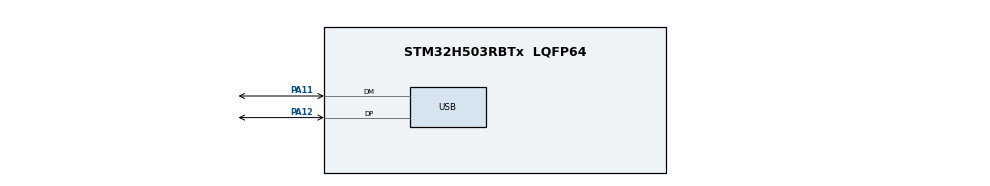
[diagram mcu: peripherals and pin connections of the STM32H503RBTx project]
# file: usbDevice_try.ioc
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Mcu.Family=STM32H5
Mcu.Name=STM32H503RBTx
Mcu.Package=LQFP64
NVIC.PriorityGroup=NVIC_PRIORITYGROUP_4
NVIC.USB_DRD_FS_IRQn=true\:0\:0\:false\:false\:true\:true\:true\:true
PA11.Mode=Device
PA11.Signal=USB_DM
PA12.Mode=Device
PA12.Signal=USB_DP
ProjectManager.HeapSize=0x600
ProjectManager.StackSize=0x800
ProjectManager.TargetToolchain=STM32CubeIDE
RCC.ADCFreq_Value=64000000
RCC.AHBFreq_Value=64000000
RCC.APB1Freq_Value=64000000
RCC.APB1TimFreq_Value=64000000
RCC.APB2Freq_Value=64000000
RCC.APB2TimFreq_Value=64000000
RCC.APB3Freq_Value=64000000
RCC.CSI_VALUE=4000000
RCC.CortexFreq_Value=64000000
RCC.EPOD_VALUE=32000000
RCC.HCLKFreq_Value=64000000
RCC.HSE_VALUE=25000000
RCC.HSI48_VALUE=48000000
RCC.HSI_VALUE=64000000
RCC.LSE_VALUE=32768
RCC.LSIRC_VALUE=32000
RCC.PLL1P=8
RCC.PLLM=8
RCC.PLLN=128
RCC.PLLSourceVirtual=RCC_PLL1_SOURCE_HSI
RCC.SYSCLKFreq_VALUE=64000000
RCC.SYSCLKSource=RCC_SYSCLKSOURCE_PLLCLK
RCC.USBFreq_Value=48000000
RCC.VCOOutputFreq_Value=512000000
USB.VirtualMode=Device_Only
VP_BOOTPATH_VS_BOOTPATH.Mode=BP_Activate
VP_CORTEX_M33_NS_VS_Hclk.Mode=Hclk_Mode
VP_MEMORYMAP_VS_MEMORYMAP.Mode=CurAppReg
VP_PWR_VS_DBSignals.Mode=DisableDeadBatterySignals
VP_PWR_VS_LPOM.Mode=PowerOptimisation
VP_PWR_VS_SECSignals.Mode=Security/Privilege
board=custom

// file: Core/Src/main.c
/* USER CODE BEGIN Header */
/**
 ******************************************************************************
 * @file           : main.c
 * @brief          : Main program body
 ******************************************************************************
 * @attention
 *
 * Copyright (c) 2024 STMicroelectronics.
 * All rights reserved.
 *
 * This software is licensed under terms that can be found in the LICENSE file
 * in the root directory of this software component.
 * If no LICENSE file comes with this software, it is provided AS-IS.
 *
 ******************************************************************************
 */
/* USER CODE END Header */
#include "main.h"

/* USER CODE BEGIN Includes */
#include "usbd_core.h"
#include "usbd_cdc.h"
#include "usbd_cdc_if.h"
#include "usbd_hid.h"
#include "usbd_desc.h"
#include "usbd_composite_builder.h"
/* USER CODE END Includes */

PCD_HandleTypeDef hpcd_USB_DRD_FS;

/* USER CODE BEGIN PV */
uint8_t CDC_EpAdd_Inst[3] = {CDC_IN_EP, CDC_OUT_EP, CDC_CMD_EP}; 	/* CDC Endpoint Addresses array */
uint8_t HID_EpAdd_Inst = HID_EPIN_ADDR;								/* HID Endpoint Address array */

USBD_HandleTypeDef hUsbDeviceFS;

uint8_t hid_report_buffer[4];

uint8_t HID_InstID = 0, CDC_InstID = 0;
/* USER CODE END PV */

void SystemClock_Config(void);
static void MX_GPIO_Init(void);

int main(void)
{

	/* USER CODE BEGIN 1 */
	hid_report_buffer[0] = 0;
	hid_report_buffer[1] = 100;
	hid_report_buffer[2] = 0;
	hid_report_buffer[3] = 0;
	/* USER CODE END 1 */

	/* MCU Configuration--------------------------------------------------------*/

	/* Reset of all peripherals, Initializes the Flash interface and the Systick. */
	HAL_Init();

	/* Configure the system clock */
	SystemClock_Config();

	/* Initialize all configured peripherals */
	MX_GPIO_Init();
	/* USER CODE BEGIN 2 */
	/* Initialize the USB Device Library */
	if(USBD_Init(&hUsbDeviceFS, &Class_Desc, 0) != USBD_OK)
		Error_Handler();

//	/* Store HID Instance Class ID */
//	HID_InstID = hUsbDeviceFS.classId;
//
//	/* Register the HID Class */
//	if(USBD_RegisterClassComposite(&hUsbDeviceFS, USBD_HID_CLASS, CLASS_TYPE_HID, &HID_EpAdd_Inst) != USBD_OK)
//		Error_Handler();

	/* Store the HID Class */
	CDC_InstID = hUsbDeviceFS.classId;

	/* Register CDC Class First Instance */
	if(USBD_RegisterClassComposite(&hUsbDeviceFS, USBD_CDC_CLASS, CLASS_TYPE_CDC, CDC_EpAdd_Inst) != USBD_OK)
		Error_Handler();

	/* Add CDC Interface Class */
	if (USBD_CMPSIT_SetClassID(&hUsbDeviceFS, CLASS_TYPE_CDC, 0) != 0xFF)
	{
		USBD_CDC_RegisterInterface(&hUsbDeviceFS, &USBD_CDC_Template_fops);
	}

	USBD_Start(&hUsbDeviceFS);
	/* USER CODE END 2 */

	/* Infinite loop */
	/* USER CODE BEGIN WHILE */
	while (1)
	{
		if(HAL_GPIO_ReadPin(GPIOC, GPIO_PIN_13) == GPIO_PIN_SET)
		{
			//USBD_HID_SendReport(&hUsbDeviceFS, hid_report_buffer, 4, HID_InstID);
			USBD_CDC_TransmitPacket(&hUsbDeviceFS, CDC_InstID);
			HAL_Delay(100);
		}
		/* USER CODE END WHILE */

	}
}

void SystemClock_Config(void)
{
	RCC_OscInitTypeDef RCC_OscInitStruct = {0};
	RCC_ClkInitTypeDef RCC_ClkInitStruct = {0};

	/** Configure the main internal regulator output voltage
	 */
	__HAL_PWR_VOLTAGESCALING_CONFIG(PWR_REGULATOR_VOLTAGE_SCALE0);

	while(!__HAL_PWR_GET_FLAG(PWR_FLAG_VOSRDY)) {}

	/** Initializes the RCC Oscillators according to the specified parameters
	 * in the RCC_OscInitTypeDef structure.
	 */
	RCC_OscInitStruct.OscillatorType = RCC_OSCILLATORTYPE_HSI48|RCC_OSCILLATORTYPE_CSI;
	RCC_OscInitStruct.HSI48State = RCC_HSI48_ON;
	RCC_OscInitStruct.CSIState = RCC_CSI_ON;
	RCC_OscInitStruct.CSICalibrationValue = RCC_CSICALIBRATION_DEFAULT;
	RCC_OscInitStruct.PLL.PLLState = RCC_PLL_ON;
	RCC_OscInitStruct.PLL.PLLSource = RCC_PLL1_SOURCE_CSI;
	RCC_OscInitStruct.PLL.PLLM = 1;
	RCC_OscInitStruct.PLL.PLLN = 125;
	RCC_OscInitStruct.PLL.PLLP = 2;
	RCC_OscInitStruct.PLL.PLLQ = 2;
	RCC_OscInitStruct.PLL.PLLR = 2;
	RCC_OscInitStruct.PLL.PLLRGE = RCC_PLL1_VCIRANGE_2;
	RCC_OscInitStruct.PLL.PLLVCOSEL = RCC_PLL1_VCORANGE_WIDE;
	RCC_OscInitStruct.PLL.PLLFRACN = 0;
	if (HAL_RCC_OscConfig(&RCC_OscInitStruct) != HAL_OK)
	{
		Error_Handler();
	}

	/** Initializes the CPU, AHB and APB buses clocks
	 */
	RCC_ClkInitStruct.ClockType = RCC_CLOCKTYPE_HCLK|RCC_CLOCKTYPE_SYSCLK
			|RCC_CLOCKTYPE_PCLK1|RCC_CLOCKTYPE_PCLK2
			|RCC_CLOCKTYPE_PCLK3;
	RCC_ClkInitStruct.SYSCLKSource = RCC_SYSCLKSOURCE_PLLCLK;
	RCC_ClkInitStruct.AHBCLKDivider = RCC_SYSCLK_DIV1;
	RCC_ClkInitStruct.APB1CLKDivider = RCC_HCLK_DIV1;
	RCC_ClkInitStruct.APB2CLKDivider = RCC_HCLK_DIV1;
	RCC_ClkInitStruct.APB3CLKDivider = RCC_HCLK_DIV1;

	if (HAL_RCC_ClockConfig(&RCC_ClkInitStruct, FLASH_LATENCY_5) != HAL_OK)
	{
		Error_Handler();
	}
}

void MX_USB_PCD_Init(void)
{

	hpcd_USB_DRD_FS.Instance = USB_DRD_FS;
	hpcd_USB_DRD_FS.Init.dev_endpoints = 8;
	hpcd_USB_DRD_FS.Init.speed = USBD_FS_SPEED;
	hpcd_USB_DRD_FS.Init.phy_itface = PCD_PHY_EMBEDDED;
	hpcd_USB_DRD_FS.Init.Sof_enable = DISABLE;
	hpcd_USB_DRD_FS.Init.low_power_enable = DISABLE;
	hpcd_USB_DRD_FS.Init.lpm_enable = DISABLE;
	hpcd_USB_DRD_FS.Init.battery_charging_enable = DISABLE;
	hpcd_USB_DRD_FS.Init.vbus_sensing_enable = DISABLE;
	hpcd_USB_DRD_FS.Init.bulk_doublebuffer_enable = DISABLE;
	hpcd_USB_DRD_FS.Init.iso_singlebuffer_enable = DISABLE;
	if (HAL_PCD_Init(&hpcd_USB_DRD_FS) != HAL_OK)
	{
		Error_Handler();
	}

}

static void MX_GPIO_Init(void)
{
	GPIO_InitTypeDef GPIO_InitStruct = {0};

	/* GPIO Ports Clock Enable */
	__HAL_RCC_GPIOC_CLK_ENABLE();
	__HAL_RCC_GPIOA_CLK_ENABLE();

	/*Configure GPIO pin : PC13 */
	GPIO_InitStruct.Pin = GPIO_PIN_13;
	GPIO_InitStruct.Mode = GPIO_MODE_INPUT;
	GPIO_InitStruct.Pull = GPIO_NOPULL;
	HAL_GPIO_Init(GPIOC, &GPIO_InitStruct);

}

void Error_Handler(void)
{
	__disable_irq();
	while (1)
	{
	}
}
